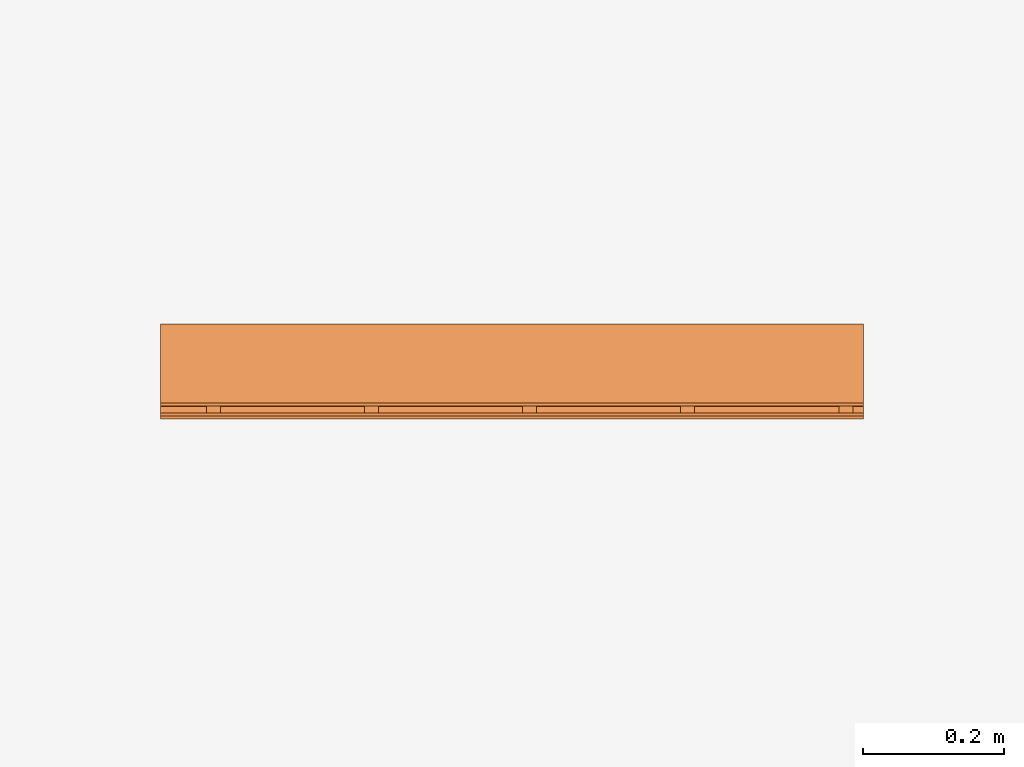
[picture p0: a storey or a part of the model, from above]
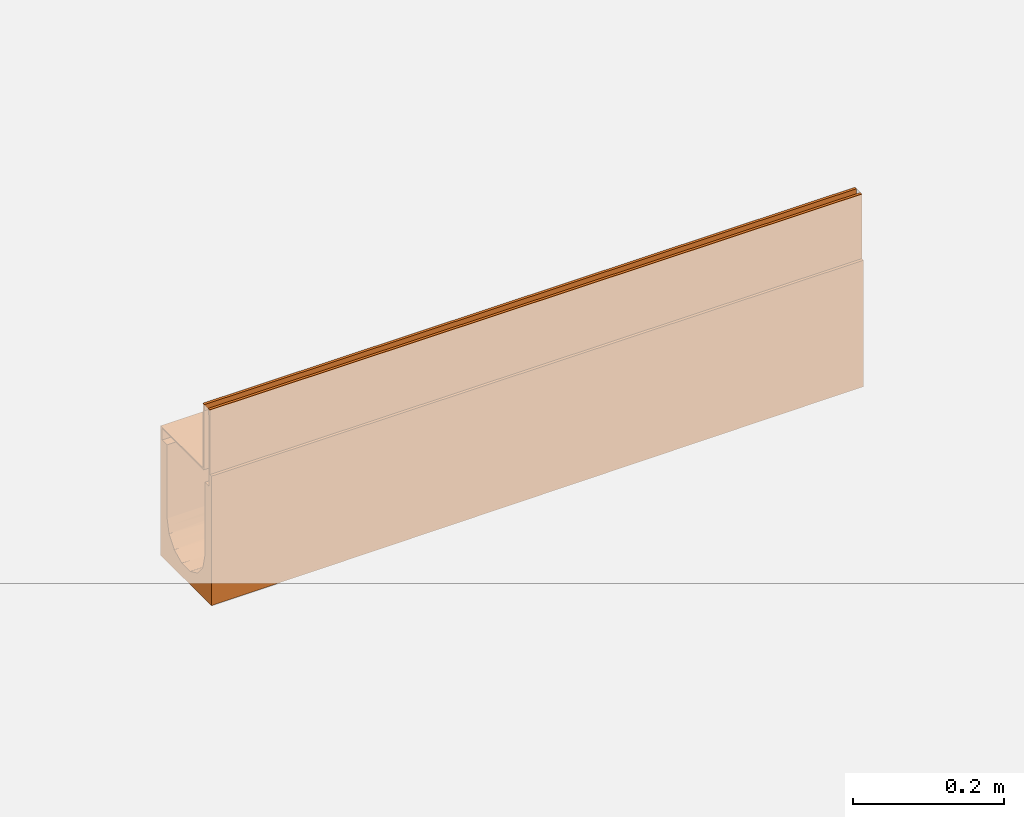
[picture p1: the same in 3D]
Properties of the parts of a building model (IFC2X3)

# File
Description: ViewDefinition [CoordinationView]
File name: 23012 - No 12 Sloping Channel - 1000mm LG - Invert Depth 185-190mm.ifc
Time: 2013-10-31T17:26:53
Written by: Autodesk Revit 2013
Made in: 20120221_2030(x64)

# IfcProject, Project Number
LongName: Project Name; Phase: Project Status

# IfcSite, Default
RefLatitude: 42, 21, 30, 344238; RefLongitude: -71, -3, -35, -194702; RefElevation: 0 mm

# IfcBuilding
Pset_BuildingCommon - NumberOfStoreys: 1
Other - Project Address: ## Street City, State Zip; Project Name: Project Name; Client Name: Owner; Project Number: Project Number; Project Status: Project Status; Project Issue Date: Issue Date

# IfcBuildingStorey, Level 1
LongName: Level 1; Elevation: 0 mm
Constraints - Elevation Base: 0; Elevation: 0 mm
Graphics - Symbol: M_Level Head - Circle: M_Level Head - Circle; Line Pattern: Center; Line Weight: 1; Color: 0; Symbol at End 2 Default: yes; Symbol at End 1 Default: no
Dimensions - Computation Height: 0 mm
Identity Data - Name: Level 1; Building Story: yes; Structural: no

# IfcBuildingElementProxy: 23012 - No 12 Sloping Channel - 1000mm LG - Invert Depth 185/190mm, Civil-Drainage-Channel-ACO-MultiDrain-M100D-Brickslot-Channel-System:23012 - No 12 Sloping Channel - 1000mm LG - Invert Depth 185/190mm:23012 - No 12 Sloping Channel - 1000mm LG - Invert Depth 185/190mm:196059
In: Level 1
Material: Steel, Galvanized, Vienite® Synthetic Resin Concrete
Construction - 23404_Universal Endcap (Male End): no; 23465_Load Class D400_Brickslot Grating_Galvanized Steel_1000mm Long: yes; 23462_Load Class C250_Brickslot Access Unit_Galvanised Steel_500mm Long: no; 23461_Load Class C250_Brickslot Grating_Galvanized Steel_500mm Long: no; 23466_Load Class D400_Brickslot Grating_Galvanized Steel_500mm Long: no; 23467_Load Class D400_Brickslot Access Unit_Galvanised Steel_500mm Long: no; 23460_Load Class C250_Brickslot Grating_Galvanized Steel_1000mm Long: no; 23404_Universal Endcap (Female End): no; Constant Depth Channel: no; Constant Depth Junction Channel: no; Shallow Depth Channel with seal: no; Shallow Depth Channel: no; Sloping Channel: yes; 23410_Sump Unit: no
Phasing - Phase Created: New Construction
Constraints - Moves With Nearby Elements: no; Level: Level: Level 1
Dimensions - FloorCut_Length: -1000 mm; EndCap Position: 1000 mm; Brickslot Access Unit Void Depth: -6500 mm; Brickslot Access Unit Void Bottom Depth: -6605 mm; Brickslot Void Length: 1000 mm; Brickslot Void Depth: 0 mm; Volume: 10601218 mm3; Custom_Void_length: 0 mm; Length: 1000 mm; GratingLength: -1000 mm; Length Drain: -1000 mm; Floor Cut Gap: 105 mm; SlopingEndOverallDepth: 210 mm; FloorCut_Width: 135 mm; EndCap_Height: 210 mm; SlopingEndInvertDepth: 140 mm; Access_Custom_Void_Length: 0 mm; ShallowInvDepth: 55 mm; FloorCut_Depth: 210 mm; SlopingInvertDepth: 135 mm; ShallowOverallDepth: 75 mm; InvDepth: 130 mm; SlopingOverallDepth: 205 mm; Brickslot Access Unit Floor Cut Length: 500 mm; Depth: 200 mm
Pset_BuildingElementProxyCommon - Reference: 23012 - No 12 Sloping Channel - 1000mm LG - Invert Depth 185/190mm
General - TagNumber: 0; SerialNumber: 0
Other - Created By: www.aco.co.uk; Watermarked By: www.aco.co.uk; Revision: 1
Data - Concrete Surround Volume - Load Class D 400 - Concrete Pavement: N/A; Installation - Concrete Grade: Refer to brochure; Pre-formed Outlet Ø: N/A; Product Dimensions: 1000mm x 135mm x 205mm/210mm (LxWxH); Invert Depth: 185mm/190mm; Concrete Surround Volume - Load Class A 15 - Concrete Pavement: N/A; Channel C.S.A: N/A; Load Class: A 15 - D 400; Concrete Surround Volume - Load Class B 125 - C 250 - Concrete Pavement: N/A; Product Standard: BS EN 1433:2002, CE marked; Hydraulic Performance: http://www.aco.co.uk/download.php?id=173; Product Weight: 16.8 Kg; ACO Hydraulic Design Software: http://www.acodesign.co.uk
Model Properties - Brickslot Access Unit Product code 23462: Load Class C250 - Brickslot Access Unit Galvanised Steel - 500mm long x 105mm high - 10mm Slot - Intake area - 10000mm²/m - 6.4 Kg; Brickslot Grating Product code 23466: Load Class D400 - Brickslot Galvanised Steel - 500mm long x 105mm high - 10mm Slot - Intake area - 10000mm²/m - 3.3 Kg; End Cap Product code 23404: No 306 Universal End Cap - 135mm wide x 300mm long - Spigot Ø110mm x 50mm long - Silver - Polypropylene - 0.16kg; Brickslot Grating Product code 23465: Load Class D400 - Brickslot Galvanised Steel - 1000mm long x 105mm high - 10mm Slot - Intake area - 10000mm²/m - 6.6 Kg; Brickslot Access Unit Product code 23467: Load Class D400 - Brickslot Access Unit Galvanised Steel - 500mm long x 105mm high - 10mm Slot - Intake area - 10000mm²/m - 6.4 Kg; Brickslot Grating Product code 23460: Load Class C250 - Brickslot Galvanised Steel - 1000mm long x 105mm high - 10mm Slot - Intake area - 10000mm²/m - 6.6 Kg; Brickslot Grating Product code 23461: Load Class C250 - Brickslot Galvanised Steel - 500mm long x 105mm high - 10mm Slot - Intake area - 10000mm²/m -3.3 Kg
Identity Data - Product brochure: http://www.aco.co.uk/download.php?id=173; Watermark 1: This file is the property of ACO Technologies PLC; URL: www.aco.co.uk; Model: ACO MultiDrain MD Brickslot- M100D; Maintenance guidelines: http://www.aco.co.uk/download.php?id=173; e-mail Technical: technical@aco.co.uk; Watermarked With: BIM Manager Premium Suite; Fax: +44 (0)1462 815895; Installation guidelines: http://www.aco.co.uk/download.php?id=173; Manufacturer: ACO Technologies plc - ACO Water Management Division; Price: POA - contact ACO; e-mail Sales: customersupport@aco.co.uk; Product Page URL: http://www.aco.co.uk/product_detail.php?id=58; Address: ACO Business Park, Hitchin Road, Shefford, Bedfordshire, United Kingdom SG17 5TE; Watermark 2: This file is water marked and users are prohibited to reproduce, adapt, distribute this information; OmniClass Title: Rainwater Removal; Assembly Code: D2040; Model Description: Channel drainage system; Telephone: +44 (0)1462 816666; Product Code: 23012; Cost: 0; Assembly Description: Rain Water Drainage; Type Comments: ACO MultiDrain M100D No 12 Sloping Channel 1000mm Long; OmniClass Number: 23.70.50.24
Materials and Finishes - Edge Rail Finish: Pre-galvanised; Edge Rail Colour: Silver; Channel Colour: Brown; Channel Material: Vienite® Synthetic Resin Concrete; Edge Rail Material: Steel
Green Building Properties - Channel Recycled Material Content: 20% minimum; Edge Rail Recyclable: Fully recyclable; Edge Rail Recycled Material Content: Between 40% - 90%; Channel Recyclable: Fully recyclable

# IfcOpeningElement: Recess (2)
In: Level 1
Dimensions - Perimeter: 20000 mm; Area: 25000000 mm2; Thickness: 1000 mm; Volume: 24969760000 mm3
Constraints - Height Offset From Level: 0 mm; Room Bounding: yes; Related to Mass: no; Level: Level: Level 1
Structural - Structural: no; Enable Analytical Model: no
Phasing - Phase Created: New Construction
Construction - Function: 0; Default Thickness: 1000 mm
Analytical Properties - Heat Transfer Coefficient (U): 0.837; Absorptance: 0.1; Roughness: 1; Thermal mass: 1359800; Thermal Resistance (R): 1.19474
Graphics - Coarse Scale Fill Color: 0
Materials and Finishes - Structural Material: Earth

# IfcSlab: Floor:Generic Floor - 1000mm, Floor:Generic Floor - 1000mm:193825
In: Level 1
PredefinedType: FLOOR; Material: Earth 1000 mm
Dimensions - Perimeter: 20000 mm; Area: 25000000 mm2; Thickness: 1000 mm; Volume: 24969760000 mm3
Constraints - Height Offset From Level: 0 mm; Room Bounding: yes; Related to Mass: no; Level: Level: Level 1
Structural - Structural: no; Enable Analytical Model: no
Phasing - Phase Created: New Construction
Pset_SlabCommon - Reference: Generic Floor - 1000mm; IsExternal: no; LoadBearing: yes
Construction - Function: 0; Default Thickness: 1000 mm
Analytical Properties - Heat Transfer Coefficient (U): 0.837; Absorptance: 0.1; Roughness: 1; Thermal mass: 1359800; Thermal Resistance (R): 1.19474
Graphics - Coarse Scale Fill Color: 0
Materials and Finishes - Structural Material: Earth
